VERSION 5.7 ;
BUSBITCHARS "[]" ;

UNITS
  DATABASE MICRONS 10000 ;
END UNITS

MANUFACTURINGGRID 0.0001 ;

PROPERTYDEFINITIONS
  MACRO previous_effective_target_usage REAL ;
  MACRO expanded_util REAL ;
  LAYER LEF58_WIDTH STRING ;
END PROPERTYDEFINITIONS

LAYER well
  TYPE MASTERSLICE ;
END well

LAYER Gate
  TYPE MASTERSLICE ;
END Gate


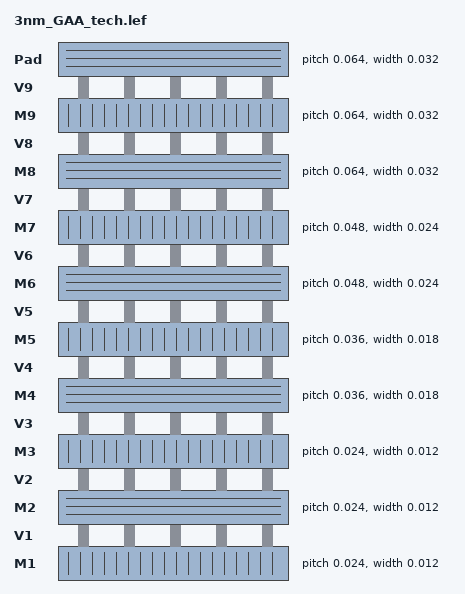
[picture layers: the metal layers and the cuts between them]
LAYER M1
  TYPE ROUTING ;
  DIRECTION VERTICAL ;
  PITCH 0.024 ;
  WIDTH 0.012 ;
  PROPERTY LEF58_WIDTH "WIDTH 0.012 WRONGDIRECTION ;" ;
END M1

LAYER V1
  TYPE CUT ;
END V1

LAYER M2
  TYPE ROUTING ;
  DIRECTION HORIZONTAL ;
  PITCH 0.024 ;
  WIDTH 0.012 ;
  PROPERTY LEF58_WIDTH "WIDTH 0.012 WRONGDIRECTION ;" ;
END M2

LAYER V2
  TYPE CUT ;
END V2

LAYER M3
  TYPE ROUTING ;
  DIRECTION VERTICAL ;
  PITCH 0.024 ;
  WIDTH 0.012 ;
  PROPERTY LEF58_WIDTH "WIDTH 0.012 WRONGDIRECTION ;" ;
END M3

LAYER V3
  TYPE CUT ;
END V3

LAYER M4
  TYPE ROUTING ;
  DIRECTION HORIZONTAL ;
  PITCH 0.036 ;
  WIDTH 0.018 ;
  PROPERTY LEF58_WIDTH "WIDTH 0.018 WRONGDIRECTION ;" ;
END M4

LAYER V4
  TYPE CUT ;
END V4

LAYER M5
  TYPE ROUTING ;
  DIRECTION VERTICAL ;
  PITCH 0.036 ;
  WIDTH 0.018 ;
  PROPERTY LEF58_WIDTH "WIDTH 0.018 WRONGDIRECTION ;" ;
END M5

LAYER V5
  TYPE CUT ;
END V5

LAYER M6
  TYPE ROUTING ;
  DIRECTION HORIZONTAL ;
  PITCH 0.048 ;
  WIDTH 0.024 ;
  PROPERTY LEF58_WIDTH "WIDTH 0.024 WRONGDIRECTION ;" ;
END M6

LAYER V6
  TYPE CUT ;
END V6

LAYER M7
  TYPE ROUTING ;
  DIRECTION VERTICAL ;
  PITCH 0.048 ;
  WIDTH 0.024 ;
  PROPERTY LEF58_WIDTH "WIDTH 0.024 WRONGDIRECTION ;" ;
END M7

LAYER V7
  TYPE CUT ;
END V7

LAYER M8
  TYPE ROUTING ;
  DIRECTION HORIZONTAL ;
  PITCH 0.064 ;
  WIDTH 0.032 ;
  PROPERTY LEF58_WIDTH "WIDTH 0.032 WRONGDIRECTION ;" ;
END M8

LAYER V8
  TYPE CUT ;
END V8

LAYER M9
  TYPE ROUTING ;
  DIRECTION VERTICAL ;
  PITCH 0.064 ;
  WIDTH 0.032 ;
  PROPERTY LEF58_WIDTH "WIDTH 0.032 WRONGDIRECTION ;" ;
END M9

LAYER V9
  TYPE CUT ;
END V9

LAYER Pad
  TYPE ROUTING ;
  DIRECTION HORIZONTAL ;
  PITCH 0.064 ;
  WIDTH 0.032 ;
  PROPERTY LEF58_WIDTH "WIDTH 0.032 WRONGDIRECTION ;" ;
END Pad

LAYER Active
  TYPE MASTERSLICE ;
END Active

LAYER fin
  TYPE MASTERSLICE ;
END fin

LAYER P_SUB
  TYPE MASTERSLICE ;
END P_SUB

LAYER Dummy
  TYPE MASTERSLICE ;
END Dummy

LAYER GCut
  TYPE MASTERSLICE ;
END GCut

LAYER Nselect
  TYPE MASTERSLICE ;
END Nselect

LAYER Pselect
  TYPE MASTERSLICE ;
END Pselect

LAYER SDT
  TYPE MASTERSLICE ;
END SDT

LAYER LIG
  TYPE MASTERSLICE ;
END LIG

LAYER LISD
  TYPE MASTERSLICE ;
END LISD

LAYER V0
  TYPE MASTERSLICE ;
END V0

LAYER SLVT
  TYPE MASTERSLICE ;
END SLVT

LAYER LVT
  TYPE MASTERSLICE ;
END LVT

LAYER SRAMDRC
  TYPE MASTERSLICE ;
END SRAMDRC

LAYER BOUNDARY
  TYPE MASTERSLICE ;
END BOUNDARY

LAYER TEXT
  TYPE MASTERSLICE ;
END TEXT

LAYER SRAMVT
  TYPE MASTERSLICE ;
END SRAMVT

LAYER text
  TYPE MASTERSLICE ;
END text

VIA Pad_M9
  LAYER M9 ;
    RECT -0.016 -0.025 0.016 0.025 ;
  LAYER V9 ;
    RECT -0.016 -0.016 0.016 0.016 ;
  LAYER Pad ;
    RECT -0.027 -0.016 0.027 0.016 ;
END Pad_M9

VIA M9_M8
  LAYER M8 ;
    RECT -0.025 -0.016 0.025 0.016 ;
  LAYER V8 ;
    RECT -0.016 -0.016 0.016 0.016 ;
  LAYER M9 ;
    RECT -0.016 -0.025 0.016 0.025 ;
END M9_M8

VIA M8_M7
  LAYER M7 ;
    RECT -0.012 -0.019 0.012 0.019 ;
  LAYER V7 ;
    RECT -0.012 -0.012 0.012 0.012 ;
  LAYER M8 ;
    RECT -0.021 -0.012 0.021 0.012 ;
END M8_M7

VIA M7_M6
  LAYER M6 ;
    RECT -0.019 -0.012 0.019 0.012 ;
  LAYER V6 ;
    RECT -0.012 -0.012 0.012 0.012 ;
  LAYER M7 ;
    RECT -0.012 -0.019 0.012 0.019 ;
END M7_M6

VIA M6_M5
  LAYER M5 ;
    RECT -0.009 -0.014 0.009 0.014 ;
  LAYER V5 ;
    RECT -0.009 -0.009 0.009 0.009 ;
  LAYER M6 ;
    RECT -0.016 -0.009 0.016 0.009 ;
END M6_M5

VIA M5_M4
  LAYER M4 ;
    RECT -0.014 -0.009 0.014 0.009 ;
  LAYER V4 ;
    RECT -0.009 -0.009 0.009 0.009 ;
  LAYER M5 ;
    RECT -0.009 -0.014 0.009 0.014 ;
END M5_M4

VIA M4_M3
  LAYER M3 ;
    RECT -0.006 -0.009 0.006 0.009 ;
  LAYER V3 ;
    RECT -0.006 -0.006 0.006 0.006 ;
  LAYER M4 ;
    RECT -0.011 -0.006 0.011 0.006 ;
END M4_M3

VIA M3_M2
  LAYER M2 ;
    RECT -0.009 -0.006 0.009 0.006 ;
  LAYER V2 ;
    RECT -0.006 -0.006 0.006 0.006 ;
  LAYER M3 ;
    RECT -0.006 -0.009 0.006 0.009 ;
END M3_M2

VIA M2_M1
  LAYER M1 ;
    RECT -0.006 -0.009 0.006 0.009 ;
  LAYER V1 ;
    RECT -0.006 -0.006 0.006 0.006 ;
  LAYER M2 ;
    RECT -0.009 -0.006 0.009 0.006 ;
END M2_M1

SITE core
  CLASS CORE ;
  SYMMETRY Y ;
  SIZE 0.042 BY 0.144 ;
END core

END LIBRARY
